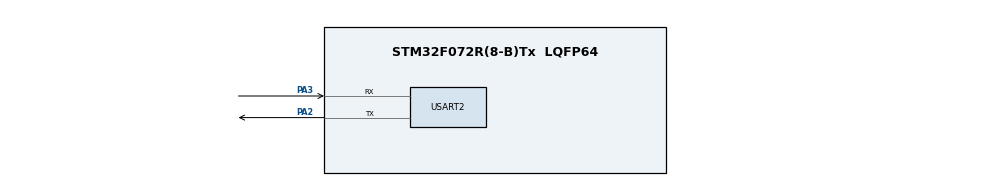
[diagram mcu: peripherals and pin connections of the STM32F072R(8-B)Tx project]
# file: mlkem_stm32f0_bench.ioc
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Mcu.Family=STM32F0
Mcu.Name=STM32F072R(8-B)Tx
Mcu.Package=LQFP64
PA2.Mode=Asynchronous
PA2.Signal=USART2_TX
PA3.Mode=Asynchronous
PA3.Signal=USART2_RX
PF0-OSC_IN.Mode=HSE-External-Oscillator
PF0-OSC_IN.Signal=RCC_OSC_IN
PF1-OSC_OUT.Mode=HSE-External-Oscillator
PF1-OSC_OUT.Signal=RCC_OSC_OUT
ProjectManager.HeapSize=0x200
ProjectManager.StackSize=0x400
ProjectManager.TargetToolchain=STM32CubeIDE
RCC.AHBFreq_Value=48000000
RCC.APB1Freq_Value=48000000
RCC.APB1TimFreq_Value=48000000
RCC.HCLKFreq_Value=48000000
RCC.PLLMUL=RCC_PLL_MUL6
RCC.PLLSourceVirtual=RCC_PLLSOURCE_HSE
RCC.SYSCLKFreq_VALUE=48000000
RCC.SYSCLKSource=RCC_SYSCLKSOURCE_PLLCLK
TIM2.AutoReloadPreload=TIM_AUTORELOAD_PRELOAD_ENABLE
TIM2.Prescaler=47
USART2.VirtualMode-Asynchronous=VM_ASYNC
VP_TIM2_VS_ClockSourceINT.Mode=Internal
board=custom

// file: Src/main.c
/* USER CODE BEGIN Header */
/**
  ******************************************************************************
  * @file           : main.c
  * @brief          : Main program body
  ******************************************************************************
  * @attention
  *
  * Copyright (c) 2026 STMicroelectronics.
  * All rights reserved.
  *
  * This software is licensed under terms that can be found in the LICENSE file
  * in the root directory of this software component.
  * If no LICENSE file comes with this software, it is provided AS-IS.
  *
  ******************************************************************************
  */
/* USER CODE END Header */
#include "main.h"

/* USER CODE BEGIN Includes */
#include <stdio.h>
#include <string.h>
#include "benchmark.h"
/* USER CODE END Includes */

TIM_HandleTypeDef htim2;

UART_HandleTypeDef huart2;

void SystemClock_Config(void);
static void MX_GPIO_Init(void);
static void MX_TIM2_Init(void);
static void MX_USART2_UART_Init(void);

int main(void)
{

  /* MCU Configuration--------------------------------------------------------*/

  /* Reset of all peripherals, Initializes the Flash interface and the Systick. */
  HAL_Init();

  /* Configure the system clock */
  SystemClock_Config();

  /* Initialize all configured peripherals */
  MX_GPIO_Init();
  MX_TIM2_Init();
  MX_USART2_UART_Init();
  /* USER CODE BEGIN 2 */
  BenchmarkResult res;
  benchmark_run(&res);
  benchmark_print_results(&res);
  /* USER CODE END 2 */

  /* Infinite loop */
  while (1)
  {

  }
}

void SystemClock_Config(void)
{
  RCC_OscInitTypeDef RCC_OscInitStruct = {0};
  RCC_ClkInitTypeDef RCC_ClkInitStruct = {0};
  RCC_PeriphCLKInitTypeDef PeriphClkInit = {0};

  /** Initializes the RCC Oscillators (HSI48 @ 48 MHz) */
  RCC_OscInitStruct.OscillatorType = RCC_OSCILLATORTYPE_HSI48;
  RCC_OscInitStruct.HSI48State = RCC_HSI48_ON;
  RCC_OscInitStruct.PLL.PLLState = RCC_PLL_NONE;
  HAL_RCC_OscConfig(&RCC_OscInitStruct);

  /** Initializes CPU, AHB and APB buses clocks (48 MHz) */
  RCC_ClkInitStruct.ClockType = RCC_CLOCKTYPE_HCLK|RCC_CLOCKTYPE_SYSCLK
                              |RCC_CLOCKTYPE_PCLK1;
  RCC_ClkInitStruct.SYSCLKSource = RCC_SYSCLKSOURCE_HSI48;
  RCC_ClkInitStruct.AHBCLKDivider = RCC_SYSCLK_DIV1;
  RCC_ClkInitStruct.APB1CLKDivider = RCC_HCLK_DIV1;
  HAL_RCC_ClockConfig(&RCC_ClkInitStruct, FLASH_LATENCY_1);

  PeriphClkInit.PeriphClockSelection = RCC_PERIPHCLK_USART2;
  PeriphClkInit.Usart2ClockSelection = RCC_USART2CLKSOURCE_PCLK1;
  HAL_RCCEx_PeriphCLKConfig(&PeriphClkInit);
}

static void MX_TIM2_Init(void)
{

  TIM_ClockConfigTypeDef sClockSourceConfig = {0};
  TIM_MasterConfigTypeDef sMasterConfig = {0};

  htim2.Instance = TIM2;
  htim2.Init.Prescaler = 47;
  htim2.Init.CounterMode = TIM_COUNTERMODE_UP;
  htim2.Init.Period = 4294967295;
  htim2.Init.ClockDivision = TIM_CLOCKDIVISION_DIV1;
  htim2.Init.AutoReloadPreload = TIM_AUTORELOAD_PRELOAD_ENABLE;
  if (HAL_TIM_Base_Init(&htim2) != HAL_OK)
  {
    Error_Handler();
  }
  sClockSourceConfig.ClockSource = TIM_CLOCKSOURCE_INTERNAL;
  if (HAL_TIM_ConfigClockSource(&htim2, &sClockSourceConfig) != HAL_OK)
  {
    Error_Handler();
  }
  sMasterConfig.MasterOutputTrigger = TIM_TRGO_RESET;
  sMasterConfig.MasterSlaveMode = TIM_MASTERSLAVEMODE_DISABLE;
  if (HAL_TIMEx_MasterConfigSynchronization(&htim2, &sMasterConfig) != HAL_OK)
  {
    Error_Handler();
  }

}

static void MX_USART2_UART_Init(void)
{

  huart2.Instance = USART2;
  huart2.Init.BaudRate = 115200;
  huart2.Init.WordLength = UART_WORDLENGTH_8B;
  huart2.Init.StopBits = UART_STOPBITS_1;
  huart2.Init.Parity = UART_PARITY_NONE;
  huart2.Init.Mode = UART_MODE_TX_RX;
  huart2.Init.HwFlowCtl = UART_HWCONTROL_NONE;
  huart2.Init.OverSampling = UART_OVERSAMPLING_16;
  huart2.Init.OneBitSampling = UART_ONE_BIT_SAMPLE_DISABLE;
  huart2.AdvancedInit.AdvFeatureInit = UART_ADVFEATURE_NO_INIT;
  if (HAL_UART_Init(&huart2) != HAL_OK)
  {
    Error_Handler();
  }

}

static void MX_GPIO_Init(void)
{

  /* GPIO Ports Clock Enable */
  __HAL_RCC_GPIOF_CLK_ENABLE();
  __HAL_RCC_GPIOA_CLK_ENABLE();

}

void Error_Handler(void)
{
  __disable_irq();
  while (1)
  {
  }
}
